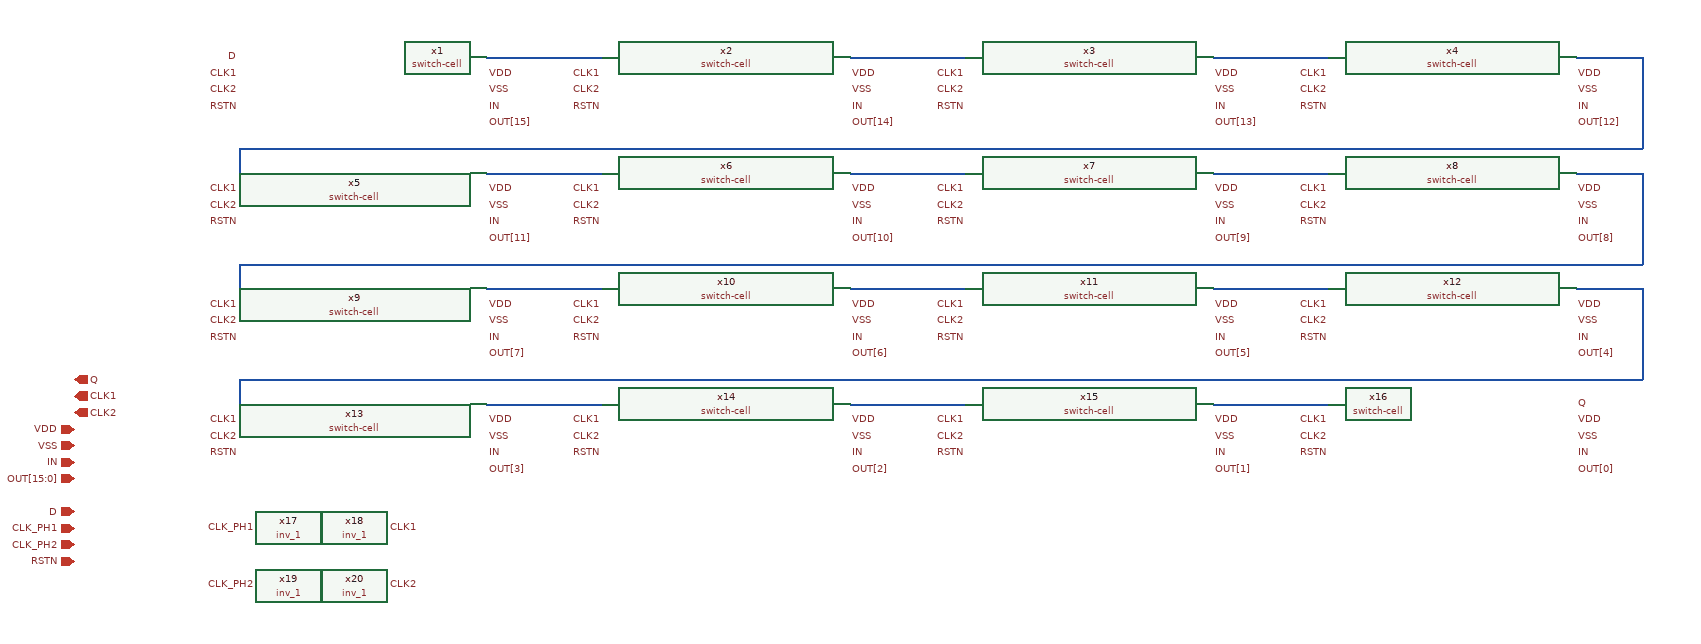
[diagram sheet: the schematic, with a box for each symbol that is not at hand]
v {xschem version=3.4.7 file_version=1.2}
G {}
K {}
V {}
S {}
E {}
N 600 -250 740 -250 {lab=#net1}
N 1040 -250 1180 -250 {lab=#net2}
N 1480 -250 1620 -250 {lab=#net3}
N 600 -390 740 -390 {lab=#net4}
N 1040 -390 1180 -390 {lab=#net5}
N 1480 -390 1620 -390 {lab=#net6}
N 600 -530 740 -530 {lab=#net7}
N 1040 -530 1180 -530 {lab=#net8}
N 1480 -530 1620 -530 {lab=#net9}
N 600 -670 740 -670 {lab=#net10}
N 1040 -670 1180 -670 {lab=#net11}
N 1480 -670 1620 -670 {lab=#net12}
N 300 -560 300 -530 {lab=#net13}
N 300 -560 2000 -560 {lab=#net13}
N 1920 -670 2000 -670 {lab=#net13}
N 2000 -670 2000 -560 {lab=#net13}
N 300 -420 300 -390 {lab=#net14}
N 300 -420 2000 -420 {lab=#net14}
N 1920 -530 2000 -530 {lab=#net14}
N 2000 -530 2000 -420 {lab=#net14}
N 1920 -390 2000 -390 {lab=#net15}
N 2000 -390 2000 -280 {lab=#net15}
N 1970 -280 2000 -280 {lab=#net15}
N 300 -280 1970 -280 {lab=#net15}
N 300 -280 300 -250 {lab=#net15}
C {lab_wire.sym} 600 -230 0 1 {name=p1 lab=VDD}
C {lab_wire.sym} 600 -210 0 1 {name=p2 lab=VSS}
C {lab_wire.sym} 600 -190 0 1 {name=p5 lab=IN}
C {lab_wire.sym} 600 -170 0 1 {name=p6 lab=OUT[3]}
C {iopin.sym} 100 -220 0 0 {name=p3 lab=VDD}
C {iopin.sym} 100 -200 0 0 {name=p7 lab=VSS}
C {iopin.sym} 100 -180 0 0 {name=p8 lab=IN}
C {iopin.sym} 100 -160 0 0 {name=p9 lab=OUT[15:0]}
C {ipin.sym} 100 -120 0 0 {name=p10 lab=D}
C {ipin.sym} 100 -60 0 0 {name=p13 lab=RSTN}
C {lab_wire.sym} 1040 -230 0 1 {name=p15 lab=VDD}
C {lab_wire.sym} 1040 -210 0 1 {name=p16 lab=VSS}
C {lab_wire.sym} 1040 -190 0 1 {name=p18 lab=IN}
C {lab_wire.sym} 1040 -170 0 1 {name=p19 lab=OUT[2]}
C {lab_wire.sym} 1480 -230 0 1 {name=p22 lab=VDD}
C {lab_wire.sym} 1480 -210 0 1 {name=p23 lab=VSS}
C {lab_wire.sym} 1480 -190 0 1 {name=p25 lab=IN}
C {lab_wire.sym} 1480 -170 0 1 {name=p26 lab=OUT[1]}
C {lab_wire.sym} 1920 -230 0 1 {name=p29 lab=VDD}
C {lab_wire.sym} 1920 -210 0 1 {name=p30 lab=VSS}
C {lab_wire.sym} 1920 -190 0 1 {name=p32 lab=IN}
C {lab_wire.sym} 1920 -170 0 1 {name=p33 lab=OUT[0]}
C {lab_wire.sym} 300 -230 0 0 {name=p4 lab=CLK1}
C {lab_wire.sym} 300 -210 0 0 {name=p11 lab=CLK2}
C {lab_wire.sym} 300 -190 0 0 {name=p17 lab=RSTN}
C {lab_wire.sym} 740 -230 0 0 {name=p21 lab=CLK1}
C {lab_wire.sym} 740 -210 0 0 {name=p24 lab=CLK2}
C {lab_wire.sym} 740 -190 0 0 {name=p27 lab=RSTN}
C {lab_wire.sym} 1180 -230 0 0 {name=p31 lab=CLK1}
C {lab_wire.sym} 1180 -210 0 0 {name=p34 lab=CLK2}
C {lab_wire.sym} 1180 -190 0 0 {name=p35 lab=RSTN}
C {lab_wire.sym} 1620 -230 0 0 {name=p43 lab=CLK1}
C {lab_wire.sym} 1620 -210 0 0 {name=p44 lab=CLK2}
C {lab_wire.sym} 1620 -190 0 0 {name=p45 lab=RSTN}
C {lab_wire.sym} 600 -370 0 1 {name=p38 lab=VDD}
C {lab_wire.sym} 600 -350 0 1 {name=p39 lab=VSS}
C {lab_wire.sym} 600 -330 0 1 {name=p47 lab=IN}
C {lab_wire.sym} 600 -310 0 1 {name=p48 lab=OUT[7]}
C {lab_wire.sym} 1040 -370 0 1 {name=p50 lab=VDD}
C {lab_wire.sym} 1040 -350 0 1 {name=p51 lab=VSS}
C {lab_wire.sym} 1040 -330 0 1 {name=p52 lab=IN}
C {lab_wire.sym} 1040 -310 0 1 {name=p53 lab=OUT[6]}
C {lab_wire.sym} 1480 -370 0 1 {name=p54 lab=VDD}
C {lab_wire.sym} 1480 -350 0 1 {name=p55 lab=VSS}
C {lab_wire.sym} 1480 -330 0 1 {name=p56 lab=IN}
C {lab_wire.sym} 1480 -310 0 1 {name=p57 lab=OUT[5]}
C {lab_wire.sym} 1920 -370 0 1 {name=p58 lab=VDD}
C {lab_wire.sym} 1920 -350 0 1 {name=p59 lab=VSS}
C {lab_wire.sym} 1920 -330 0 1 {name=p60 lab=IN}
C {lab_wire.sym} 1920 -310 0 1 {name=p61 lab=OUT[4]}
C {lab_wire.sym} 300 -370 0 0 {name=p62 lab=CLK1}
C {lab_wire.sym} 300 -350 0 0 {name=p63 lab=CLK2}
C {lab_wire.sym} 300 -330 0 0 {name=p64 lab=RSTN}
C {lab_wire.sym} 740 -370 0 0 {name=p66 lab=CLK1}
C {lab_wire.sym} 740 -350 0 0 {name=p67 lab=CLK2}
C {lab_wire.sym} 740 -330 0 0 {name=p68 lab=RSTN}
C {lab_wire.sym} 1180 -370 0 0 {name=p70 lab=CLK1}
C {lab_wire.sym} 1180 -350 0 0 {name=p71 lab=CLK2}
C {lab_wire.sym} 1180 -330 0 0 {name=p72 lab=RSTN}
C {lab_wire.sym} 1620 -370 0 0 {name=p74 lab=CLK1}
C {lab_wire.sym} 1620 -350 0 0 {name=p75 lab=CLK2}
C {lab_wire.sym} 1620 -330 0 0 {name=p76 lab=RSTN}
C {lab_wire.sym} 600 -510 0 1 {name=p78 lab=VDD}
C {lab_wire.sym} 600 -490 0 1 {name=p79 lab=VSS}
C {lab_wire.sym} 600 -470 0 1 {name=p80 lab=IN}
C {lab_wire.sym} 600 -450 0 1 {name=p81 lab=OUT[11]}
C {lab_wire.sym} 1040 -510 0 1 {name=p83 lab=VDD}
C {lab_wire.sym} 1040 -490 0 1 {name=p84 lab=VSS}
C {lab_wire.sym} 1040 -470 0 1 {name=p85 lab=IN}
C {lab_wire.sym} 1040 -450 0 1 {name=p86 lab=OUT[10]}
C {lab_wire.sym} 1480 -510 0 1 {name=p87 lab=VDD}
C {lab_wire.sym} 1480 -490 0 1 {name=p88 lab=VSS}
C {lab_wire.sym} 1480 -470 0 1 {name=p89 lab=IN}
C {lab_wire.sym} 1480 -450 0 1 {name=p90 lab=OUT[9]}
C {lab_wire.sym} 1920 -510 0 1 {name=p91 lab=VDD}
C {lab_wire.sym} 1920 -470 0 1 {name=p93 lab=IN}
C {lab_wire.sym} 1920 -450 0 1 {name=p94 lab=OUT[8]}
C {lab_wire.sym} 300 -510 0 0 {name=p95 lab=CLK1}
C {lab_wire.sym} 300 -490 0 0 {name=p96 lab=CLK2}
C {lab_wire.sym} 300 -470 0 0 {name=p97 lab=RSTN}
C {lab_wire.sym} 740 -510 0 0 {name=p99 lab=CLK1}
C {lab_wire.sym} 740 -490 0 0 {name=p100 lab=CLK2}
C {lab_wire.sym} 740 -470 0 0 {name=p101 lab=RSTN}
C {lab_wire.sym} 1180 -510 0 0 {name=p103 lab=CLK1}
C {lab_wire.sym} 1180 -490 0 0 {name=p104 lab=CLK2}
C {lab_wire.sym} 1180 -470 0 0 {name=p105 lab=RSTN}
C {lab_wire.sym} 1620 -510 0 0 {name=p107 lab=CLK1}
C {lab_wire.sym} 1620 -490 0 0 {name=p108 lab=CLK2}
C {lab_wire.sym} 1620 -470 0 0 {name=p109 lab=RSTN}
C {lab_wire.sym} 600 -650 0 1 {name=p111 lab=VDD}
C {lab_wire.sym} 600 -630 0 1 {name=p112 lab=VSS}
C {lab_wire.sym} 600 -610 0 1 {name=p113 lab=IN}
C {lab_wire.sym} 600 -590 0 1 {name=p114 lab=OUT[15]}
C {lab_wire.sym} 300 -670 0 0 {name=p115 lab=D}
C {lab_wire.sym} 1040 -650 0 1 {name=p116 lab=VDD}
C {lab_wire.sym} 1040 -630 0 1 {name=p117 lab=VSS}
C {lab_wire.sym} 1040 -610 0 1 {name=p118 lab=IN}
C {lab_wire.sym} 1040 -590 0 1 {name=p119 lab=OUT[14]}
C {lab_wire.sym} 1480 -650 0 1 {name=p120 lab=VDD}
C {lab_wire.sym} 1480 -630 0 1 {name=p121 lab=VSS}
C {lab_wire.sym} 1480 -610 0 1 {name=p122 lab=IN}
C {lab_wire.sym} 1480 -590 0 1 {name=p123 lab=OUT[13]}
C {lab_wire.sym} 1920 -650 0 1 {name=p124 lab=VDD}
C {lab_wire.sym} 1920 -630 0 1 {name=p125 lab=VSS}
C {lab_wire.sym} 1920 -610 0 1 {name=p126 lab=IN}
C {lab_wire.sym} 1920 -590 0 1 {name=p127 lab=OUT[12]}
C {lab_wire.sym} 300 -650 0 0 {name=p128 lab=CLK1}
C {lab_wire.sym} 300 -630 0 0 {name=p129 lab=CLK2}
C {lab_wire.sym} 300 -610 0 0 {name=p130 lab=RSTN}
C {lab_wire.sym} 740 -650 0 0 {name=p132 lab=CLK1}
C {lab_wire.sym} 740 -630 0 0 {name=p133 lab=CLK2}
C {lab_wire.sym} 740 -610 0 0 {name=p134 lab=RSTN}
C {lab_wire.sym} 1180 -650 0 0 {name=p136 lab=CLK1}
C {lab_wire.sym} 1180 -630 0 0 {name=p137 lab=CLK2}
C {lab_wire.sym} 1180 -610 0 0 {name=p138 lab=RSTN}
C {lab_wire.sym} 1620 -650 0 0 {name=p140 lab=CLK1}
C {lab_wire.sym} 1620 -630 0 0 {name=p141 lab=CLK2}
C {lab_wire.sym} 1620 -610 0 0 {name=p142 lab=RSTN}
C {libs/core_switch-matrix/switch-cell/switch-cell.sym} 450 -630 0 0 {name=x1}
C {libs/core_switch-matrix/switch-cell/switch-cell.sym} 890 -630 0 0 {name=x2}
C {libs/core_switch-matrix/switch-cell/switch-cell.sym} 1330 -630 0 0 {name=x3}
C {libs/core_switch-matrix/switch-cell/switch-cell.sym} 1770 -630 0 0 {name=x4}
C {libs/core_switch-matrix/switch-cell/switch-cell.sym} 450 -490 0 0 {name=x5}
C {libs/core_switch-matrix/switch-cell/switch-cell.sym} 890 -490 0 0 {name=x6}
C {libs/core_switch-matrix/switch-cell/switch-cell.sym} 1330 -490 0 0 {name=x7}
C {libs/core_switch-matrix/switch-cell/switch-cell.sym} 1770 -490 0 0 {name=x8}
C {libs/core_switch-matrix/switch-cell/switch-cell.sym} 450 -350 0 0 {name=x9}
C {libs/core_switch-matrix/switch-cell/switch-cell.sym} 890 -350 0 0 {name=x10}
C {libs/core_switch-matrix/switch-cell/switch-cell.sym} 1330 -350 0 0 {name=x11}
C {libs/core_switch-matrix/switch-cell/switch-cell.sym} 1770 -350 0 0 {name=x12}
C {libs/core_switch-matrix/switch-cell/switch-cell.sym} 450 -210 0 0 {name=x13}
C {libs/core_switch-matrix/switch-cell/switch-cell.sym} 890 -210 0 0 {name=x14}
C {libs/core_switch-matrix/switch-cell/switch-cell.sym} 1330 -210 0 0 {name=x15}
C {libs/core_switch-matrix/switch-cell/switch-cell.sym} 1770 -210 0 0 {name=x16}
C {lab_wire.sym} 320 -100 0 0 {name=p12 lab=CLK_PH1}
C {lab_wire.sym} 320 -30 0 0 {name=p40 lab=CLK_PH2}
C {lab_wire.sym} 480 -100 0 1 {name=p41 lab=CLK1}
C {lab_wire.sym} 480 -30 0 1 {name=p42 lab=CLK2}
C {ipin.sym} 100 -100 0 0 {name=p14 lab=CLK_PH1}
C {ipin.sym} 100 -80 0 0 {name=p49 lab=CLK_PH2}
C {lab_wire.sym} 1920 -250 0 1 {name=p82 lab=Q}
C {opin.sym} 100 -280 0 0 {name=p144 lab=Q}
C {opin.sym} 100 -260 0 0 {name=p145 lab=CLK1}
C {opin.sym} 100 -240 0 0 {name=p146 lab=CLK2}
C {libs/gf180mcu_fd_sc_mcu9t5v0_symbols/inv_1.sym} 360 -100 0 0 {name=x17 VGND=VSSd VNB=VDDd VPB=VSSd VPWR=VDDd prefix=gf180mcu_fd_sc_mcu9t5v0__ }
C {libs/gf180mcu_fd_sc_mcu9t5v0_symbols/inv_1.sym} 440 -100 0 0 {name=x18 VGND=VSSd VNB=VDDd VPB=VSSd VPWR=VDDd prefix=gf180mcu_fd_sc_mcu9t5v0__ }
C {libs/gf180mcu_fd_sc_mcu9t5v0_symbols/inv_1.sym} 360 -30 0 0 {name=x19 VGND=VSSd VNB=VDDd VPB=VSSd VPWR=VDDd prefix=gf180mcu_fd_sc_mcu9t5v0__ }
C {libs/gf180mcu_fd_sc_mcu9t5v0_symbols/inv_1.sym} 440 -30 0 0 {name=x20 VGND=VSSd VNB=VDDd VPB=VSSd VPWR=VDDd prefix=gf180mcu_fd_sc_mcu9t5v0__ }
C {lab_wire.sym} 1920 -490 0 1 {name=p20 lab=VSS}
